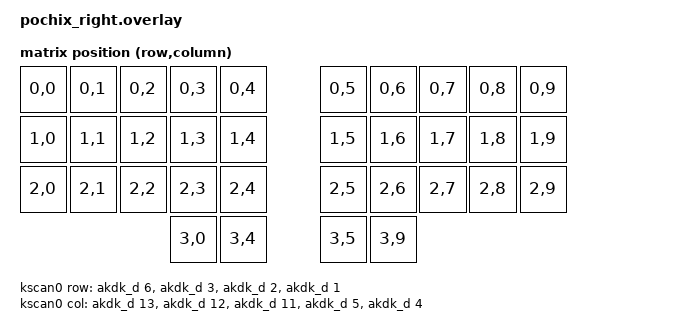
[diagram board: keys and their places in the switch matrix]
#include <dt-bindings/zmk/matrix_transform.h>
#include <input/processors.dtsi>
#include <dt-bindings/zmk/input_transform.h>
#include "layouts.dtsi"

/ {
    chosen {
        zmk,physical-layout = &physical_layout0;
    };

    default_transform: keymap_transform_0 {
        compatible = "zmk,matrix-transform";
        columns = <10>;
        rows = <4>;
        map = <
            RC(0,0) RC(0,1) RC(0,2) RC(0,3) RC(0,4) RC(0,5) RC(0,6) RC(0,7) RC(0,8) RC(0,9)
            RC(1,0) RC(1,1) RC(1,2) RC(1,3) RC(1,4) RC(1,5) RC(1,6) RC(1,7) RC(1,8) RC(1,9)
            RC(2,0) RC(2,1) RC(2,2) RC(2,3) RC(2,4) RC(2,5) RC(2,6) RC(2,7) RC(2,8) RC(2,9)
            RC(3,0) RC(3,4) RC(3,5) RC(3,9)
        >;
        col-offset = <5>;
    };

    kscan0: kscan {
        compatible = "zmk,kscan-gpio-matrix";
        wakeup-source;

        diode-direction = "col2row";
        row-gpios
            = <&akdk_d 6 (GPIO_ACTIVE_HIGH | GPIO_PULL_DOWN)>
            ,<&akdk_d 3 (GPIO_ACTIVE_HIGH | GPIO_PULL_DOWN)>
            ,<&akdk_d 2 (GPIO_ACTIVE_HIGH | GPIO_PULL_DOWN)>
            ,<&akdk_d 1 (GPIO_ACTIVE_HIGH | GPIO_PULL_DOWN)>
            ;
        col-gpios
            = <&akdk_d 13 GPIO_ACTIVE_HIGH>
            ,<&akdk_d 12 GPIO_ACTIVE_HIGH>
            ,<&akdk_d 11 GPIO_ACTIVE_HIGH>
            ,<&akdk_d 5 GPIO_ACTIVE_HIGH>
            ,<&akdk_d 4 GPIO_ACTIVE_HIGH>
            ;
    };

    trackball_listener: trackball_listener {
        compatible = "zmk,input-listener";
        device = <&trackball>;
        
        // 通常時の移動設定（XY反転と感度調整）
        input-processors = 
            <&zip_xy_transform (INPUT_TRANSFORM_X_INVERT | INPUT_TRANSFORM_Y_INVERT)>,
            <&zip_x_scaler 3 5>, 
            <&zip_y_scaler 9 10>;

        // レイヤー3でのスクロール設定
        scroller {
            layers = <3>;
            input-processors = 
                <&zip_xy_to_scroll_mapper>, 
                <&zip_scroll_transform (INPUT_TRANSFORM_X_INVERT)>, 
                <&zip_scroll_scaler 1 128>;
            process-next;
        };
    };

    split_inputs {
        #address-cells = <1>;
        #size-cells =
};

